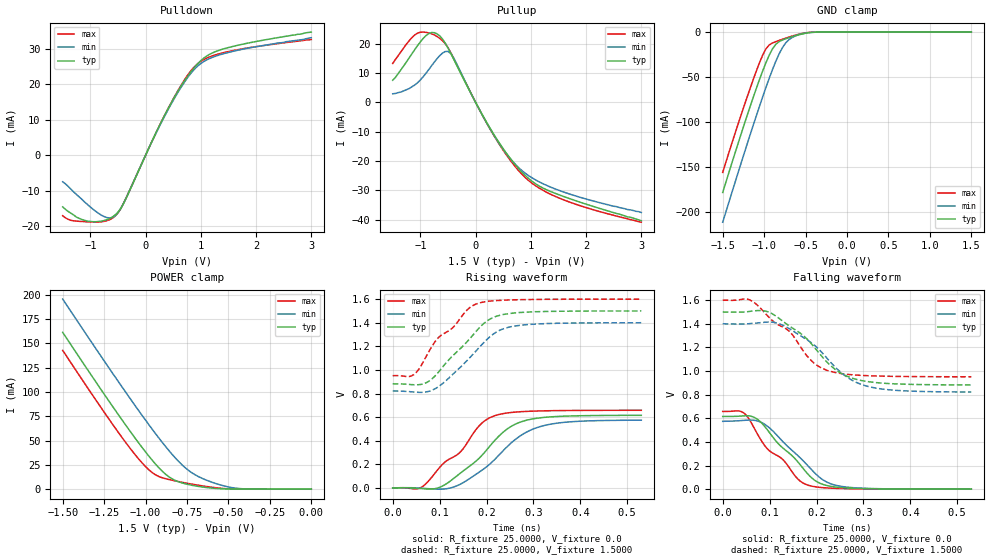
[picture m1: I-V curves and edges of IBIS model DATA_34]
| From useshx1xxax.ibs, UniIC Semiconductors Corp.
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|When TDQS is enabled, NU_TDQS is a output with terminal resistance;
|When TDQS is disabled, NU_TDQS is a DM;
|   Model DATA_34
[Model]  DATA_34
Model_type   I/O
Polarity   Non-Inverting
Enable   Active-High
Vinl =   0.600000V
Vinh =   0.900000V
Vmeas =   0.750000V
Rref =   25.0000000
Vref =   0.7500000V
C_comp   1.3900pF   1.3640pF   1.5600pF
[Temperature Range]   25.0000   0.1250k   -55.0000
[Voltage Range]   1.5000V   1.4000V   1.6000V
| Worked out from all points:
|   slope of the pulldown table from 0 to 0.225 V, typ, clamps not added: 29.8 ohm
|   slope of the pullup table from 0 to 0.225 V, typ, clamps not added: 29.6 ohm
|   GND clamp passes 1 mA (typ) near -0.48 V on its own axis
|   POWER clamp passes 1 mA (typ) near -0.59 V on its own axis
|   rising waveform, R_fixture 25.0000, V_fixture 0.0: 20-80 % time 98.2ps typ, 102ps min, 93ps max; typ from 0 V to 0.615 V
|   rising waveform, R_fixture 25.0000, V_fixture 1.5000: 20-80 % time 86.9ps typ, 86.9ps min, 83.4ps max; typ from 0.882 V to 1.5 V
|   falling waveform, R_fixture 25.0000, V_fixture 0.0: 20-80 % time 85.5ps typ, 87.2ps min, 84.7ps max; typ from 0.615 V to 0 V
|   falling waveform, R_fixture 25.0000, V_fixture 1.5000: 20-80 % time 99ps typ, 97.4ps min, 95.9ps max; typ from 1.5 V to 0.882 V
[Pulldown]
|Voltage   I(typ)   I(min)   I(max)
-1.5V     -14.6mA    -7.5mA     -17.1mA
-1.35V    -16.4mA    -9.6mA     -18.4mA
-1.05V    -18.61mA   -13.95mA   -18.83mA
-750mV    -18.45mA   -17.34mA   -18.69mA
-600mV    -17.44mA   -17.58mA   -17.78mA
-400mV    -13.69mA   -13.61mA   -13.63mA
450mV     14.38mA    14.09mA    14.45mA
700mV     20.91mA    20.57mA    21.2mA
900mV     25.09mA    24.56mA    25.26mA
1.1V      27.97mA    26.89mA    27.4mA
1.4V      30mA       28.64mA    28.94mA
3V        34.8mA     33.2mA     32.7mA
[Pullup]
|Voltage   I(typ)   I(min)   I(max)
-1.5V     7.5mA      2.9mA      13.2mA
-1.2V     15.18mA    4.7mA      21mA
-1.05V    19.29mA    6.66mA     23.54mA
-850mV    23.36mA    11.08mA    23.61mA
-700mV    23.33mA    14.78mA    22.43mA
-550mV    20.17mA    17.27mA    19.98mA
-450mV    16.69mA    16.62mA    16.92mA
350mV     -11.5mA    -11.77mA   -11.88mA
650mV     -19.65mA   -19.65mA   -20.28mA
950mV     -25.77mA   -24.83mA   -26.46mA
1.7V      -32.77mA   -31.21mA   -33.95mA
3V        -40.3mA    -37.5mA    -40.8mA
[GND_clamp]
|Voltage   I(typ)   I(min)   I(max)
-1.5V     -178.7mA   -211.8mA   -156.3mA
-1.22V    -97.06mA   -129.1mA   -76.4mA
-1.1V     -64.25mA   -94.83mA   -44.79mA
-1.02V    -43.87mA   -72.78mA   -26.14mA
-980mV    -34.46mA   -62.12mA   -18.9mA
-940mV    -25.94mA   -51.8mA    -14.39mA
-860mV    -13.68mA   -32.73mA   -10.66mA
-780mV    -8.804mA   -17.43mA   -8.022mA
-700mV    -6.175mA   -8.381mA   -5.548mA
-580mV    -2.935mA   -2.858mA   -2.33mA
-380mV    -108.7uA   -140.3uA   -50.06uA
1.5V      1.623nA    90.12nA    166.1pA
[POWER_clamp]
|Voltage   I(typ)   I(min)   I(max)
-1.5V     161.3mA    195.6mA    142.8mA
-1.22V    90.37mA    124.5mA    71.87mA
-1.04V    47.2mA     80.43mA    30.73mA
-980mV    33.96mA    66.31mA    19.9mA
-940mV    25.82mA    57.16mA    14.73mA
-880mV    15.49mA    44.03mA    10.81mA
-840mV    10.61mA    35.86mA    9.21mA
-760mV    5.492mA    21.96mA    6.413mA
-700mV    3.357mA    14.68mA    4.567mA
-520mV    282.1uA    3.064mA    565.6uA
-400mV    16.23uA    287.1uA    24.34uA
0V        1.623nA    18.77nA    210.2pA
[Ramp]
| variable   typ   min   max
dV/dt_r  0.3694/99.9524p   0.3451/0.1035n   0.3949/93.7965p
dV/dt_f  0.3712/0.1005n   0.3474/99.1792p   0.3895/97.3597p
R_load = 25.0000
[Rising Waveform]
R_fixture= 25.0000
V_fixture= 0.0
V_fixture_min= 0.0
V_fixture_max= 0.0
|time   V(typ)   V(min)   V(max)
0s        0V         0V         0V
60ps      -5.059mV   -2.078mV   2.719mV
105ps     13.96mV    -10.01mV   195.7mV
150ps     143.2mV    44.4mV     331mV
185ps     254.4mV    135.8mV    529.3mV
220ps     413mV      251.4mV    615.1mV
265ps     546.6mV    421.6mV    643.6mV
320ps     596.5mV    525.8mV    652.9mV
390ps     610.7mV    563.1mV    656.4mV
530ps     615.1mV    574.1mV    657.9mV
[Rising Waveform]
R_fixture= 25.0000
V_fixture= 1.5000
V_fixture_min= 1.4000
V_fixture_max= 1.6000
|time   V(typ)   V(min)   V(max)
0s        882.1mV    822.2mV    951.1mV
45ps      874mV      812.6mV    960.1mV
75ps      898.8mV    816.2mV    1.14V
95ps      969.1mV    851.1mV    1.263V
130ps     1.127V     969.6mV    1.365V
160ps     1.245V     1.085V     1.513V
180ps     1.336V     1.171V     1.561V
210ps     1.436V     1.29V      1.584V
255ps     1.48V      1.368V     1.593V
530ps     1.5V       1.4V       1.6V
[Falling Waveform]
R_fixture= 25.0000
V_fixture= 0.0
V_fixture_min= 0.0
V_fixture_max= 0.0
|time   V(typ)   V(min)   V(max)
0s        615.1mV    574.1mV    657.9mV
45ps      620.4mV    582.2mV    645.1mV
75ps      588.4mV    576.4mV    459.8mV
95ps      503.7mV    534.1mV    342.3mV
125ps     359.6mV    416mV      261.9mV
160ps     232mV      284.8mV    86.36mV
180ps     134.6mV    205mV      36.23mV
215ps     38.58mV    75.45mV    12.37mV
255ps     12.74mV    22.24mV    5.288mV
530ps     0V         0V         0V
[Falling Waveform]
R_fixture= 25.0000
V_fixture= 1.5000
V_fixture_min= 1.4000
V_fixture_max= 1.6000
|time   V(typ)   V(min)   V(max)
0s        1.5V       1.4V       1.6V
55ps      1.503V     1.4V       1.606V
100ps     1.496V     1.414V     1.449V
145ps     1.373V     1.351V     1.324V
180ps     1.27V      1.264V     1.126V
200ps     1.178V     1.203V     1.051V
225ps     1.065V     1.096V     1.002V
270ps     948mV      935.5mV    970.3mV
315ps     907.3mV    864.4mV    959.6mV
530ps     882.1mV    822.2mV    951.1mV
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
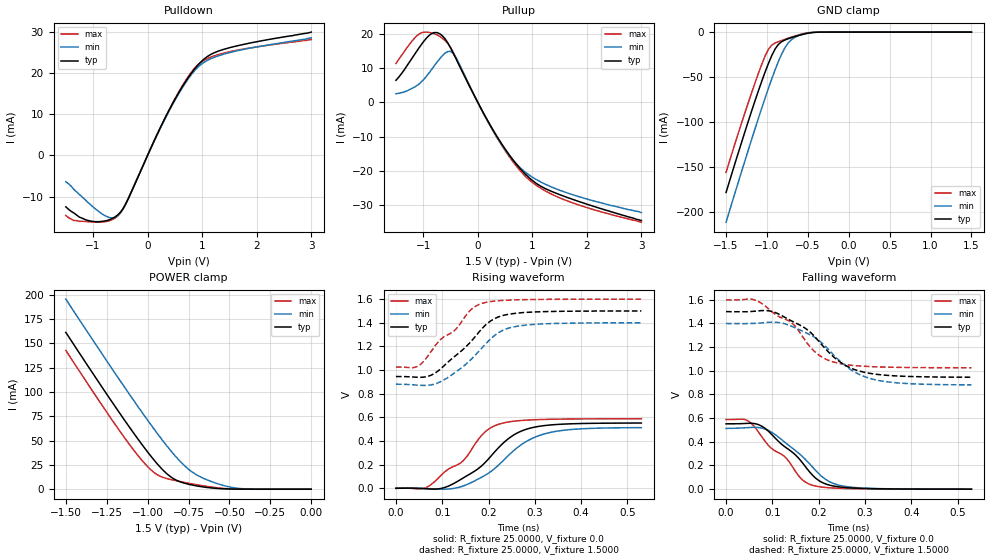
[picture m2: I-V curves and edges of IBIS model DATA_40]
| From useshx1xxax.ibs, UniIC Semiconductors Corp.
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|   Model DATA_40
[Model]  DATA_40
Model_type   I/O
Polarity   Non-Inverting
Enable   Active-High
Vinl =   0.600000V
Vinh =   0.900000V
Vmeas =   0.750000V
Rref =   25.000000
Vref =   0.7500000V
C_comp   1.3900pF   1.3640pF   1.5600pF
[Temperature Range]   25.0000   0.1250k   -55.0000
[Voltage Range]   1.5000V   1.4000V   1.6000V
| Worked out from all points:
|   slope of the pulldown table from 0 to 0.225 V, typ, clamps not added: 34.7 ohm
|   slope of the pullup table from 0 to 0.225 V, typ, clamps not added: 34.4 ohm
|   GND clamp passes 1 mA (typ) near -0.48 V on its own axis
|   POWER clamp passes 1 mA (typ) near -0.59 V on its own axis
|   rising waveform, R_fixture 25.0000, V_fixture 0.0: 20-80 % time 95.5ps typ, 99.1ps min, 91.3ps max; typ from 0 V to 0.552 V
|   rising waveform, R_fixture 25.0000, V_fixture 1.5000: 20-80 % time 86.4ps typ, 84.6ps min, 83.2ps max; typ from 0.946 V to 1.5 V
|   falling waveform, R_fixture 25.0000, V_fixture 0.0: 20-80 % time 85.1ps typ, 85.8ps min, 83.6ps max; typ from 0.552 V to 0 V
|   falling waveform, R_fixture 25.0000, V_fixture 1.5000: 20-80 % time 95.2ps typ, 94.5ps min, 94.5ps max; typ from 1.5 V to 0.946 V
[Pulldown]
|Voltage   I(typ)   I(min)   I(max)
-1.5V     -12.5mA    -6.4mA     -14.6mA
-1.35V    -14mA      -8.3mA     -15.8mA
-1.05V    -15.94mA   -11.94mA   -16.13mA
-750mV    -15.82mA   -14.85mA   -16.03mA
-600mV    -14.97mA   -15.08mA   -15.26mA
-400mV    -11.78mA   -11.71mA   -11.73mA
450mV     12.37mA    12.12mA    12.43mA
700mV     17.98mA    17.68mA    18.23mA
900mV     21.56mA    21.1mA     21.7mA
1.1V      24.01mA    23.07mA    23.5mA
1.4V      25.73mA    24.56mA    24.82mA
3V        29.9mA     28.5mA     28.1mA
[Pullup]
|Voltage   I(typ)   I(min)   I(max)
-1.5V     6.4mA      2.5mA      11.3mA
-1.05V    16.48mA    5.69mA     20.16mA
-850mV    20mA       9.46mA     20.25mA
-700mV    20.03mA    12.63mA    19.26mA
-550mV    17.36mA    14.8mA     17.18mA
-450mV    14.37mA    14.29mA    14.57mA
350mV     -9.897mA   -10.12mA   -10.22mA
650mV     -16.9mA    -16.89mA   -17.44mA
900mV     -21.4mA    -20.74mA   -22.01mA
1.2V      -24.88mA   -23.62mA   -25.52mA
1.65V     -27.83mA   -26.5mA    -28.83mA
3V        -34.5mA    -32.2mA    -35mA
[GND_clamp]
|Voltage   I(typ)   I(min)   I(max)
-1.5V     -178.7mA   -211.8mA   -156.3mA
-1.22V    -97.06mA   -129.1mA   -76.4mA
-1.1V     -64.25mA   -94.83mA   -44.79mA
-1.02V    -43.87mA   -72.78mA   -26.14mA
-980mV    -34.46mA   -62.12mA   -18.9mA
-940mV    -25.94mA   -51.8mA    -14.39mA
-860mV    -13.68mA   -32.73mA   -10.66mA
-780mV    -8.804mA   -17.43mA   -8.022mA
-700mV    -6.175mA   -8.381mA   -5.548mA
-580mV    -2.935mA   -2.858mA   -2.33mA
-380mV    -108.7uA   -140.3uA   -50.06uA
1.5V      1.623nA    90.12nA    166.1pA
[POWER_clamp]
|Voltage   I(typ)   I(min)   I(max)
-1.5V     161.3mA    195.6mA    142.8mA
-1.22V    90.37mA    124.5mA    71.87mA
-1.04V    47.2mA     80.43mA    30.73mA
-980mV    33.96mA    66.31mA    19.9mA
-940mV    25.82mA    57.16mA    14.73mA
-880mV    15.49mA    44.03mA    10.81mA
-840mV    10.61mA    35.86mA    9.21mA
-760mV    5.492mA    21.96mA    6.413mA
-700mV    3.357mA    14.68mA    4.567mA
-520mV    282.1uA    3.064mA    565.6uA
-400mV    16.23uA    287.1uA    24.34uA
0V        1.623nA    18.77nA    210.2pA
[Ramp]
| variable   typ   min   max
dV/dt_r  0.3315/96.9880p   0.3085/0.1005n   0.3529/92.4923p
dV/dt_f  0.3332/96.7909p   0.3122/96.3373p   0.3450/94.7585p
R_load = 25.0000
[Rising Waveform]
R_fixture= 25.0000
V_fixture= 0.0
V_fixture_min= 0.0
V_fixture_max= 0.0
|time   V(typ)   V(min)   V(max)
0s        0V         0V         0V
65ps      -4.097mV   -1.793mV   6.117mV
110ps     13.43mV    -6.823mV   153mV
145ps     86.52mV    19.03mV    232.1mV
180ps     172.9mV    82.84mV    423.9mV
200ps     248.7mV    128.3mV    499.6mV
225ps     356.9mV    209.1mV    545.3mV
270ps     482.4mV    366.5mV    573.1mV
325ps     532.1mV    464.6mV    582.7mV
530ps     551.8mV    512.9mV    588mV
[Rising Waveform]
R_fixture= 25.0000
V_fixture= 1.5000
V_fixture_min= 1.4000
V_fixture_max= 1.6000
|time   V(typ)   V(min)   V(max)
0s        945.6mV    881.1mV    1.025V
45ps      939mV      872.7mV    1.028V
80ps      963.9mV    877.7mV    1.179V
95ps      1.004V     898.7mV    1.253V
140ps     1.157V     1.014V     1.398V
165ps     1.254V     1.1V       1.52V
190ps     1.367V     1.205V     1.568V
225ps     1.454V     1.324V     1.587V
270ps     1.484V     1.375V     1.594V
530ps     1.5V       1.4V       1.6V
[Falling Waveform]
R_fixture= 25.0000
V_fixture= 0.0
V_fixture_min= 0.0
V_fixture_max= 0.0
|time   V(typ)   V(min)   V(max)
0s        551.8mV    512.9mV    588mV
45ps      555.8mV    519.4mV    581.8mV
80ps      525.2mV    512.8mV    427.5mV
100ps     456.3mV    477.2mV    338.4mV
130ps     349.4mV    386.4mV    261.6mV
165ps     222.5mV    275.4mV    78.27mV
190ps     105.4mV    173.1mV    29.33mV
225ps     32.55mV    59.73mV    11.23mV
265ps     11.65mV    19.21mV    4.969mV
530ps     0V         0V         0V
[Falling Waveform]
R_fixture= 25.0000
V_fixture= 1.5000
V_fixture_min= 1.4000
V_fixture_max= 1.6000
|time   V(typ)   V(min)   V(max)
0s        1.5V       1.4V       1.6V
60ps      1.503V     1.4V       1.601V
110ps     1.486V     1.409V     1.467V
145ps     1.414V     1.37V      1.394V
175ps     1.348V     1.317V     1.234V
200ps     1.251V     1.259V     1.134V
230ps     1.126V     1.143V     1.076V
270ps     1.022V     1.007V     1.047V
325ps     970.3mV    921.9mV    1.033V
530ps     945.6mV    881.1mV    1.025V
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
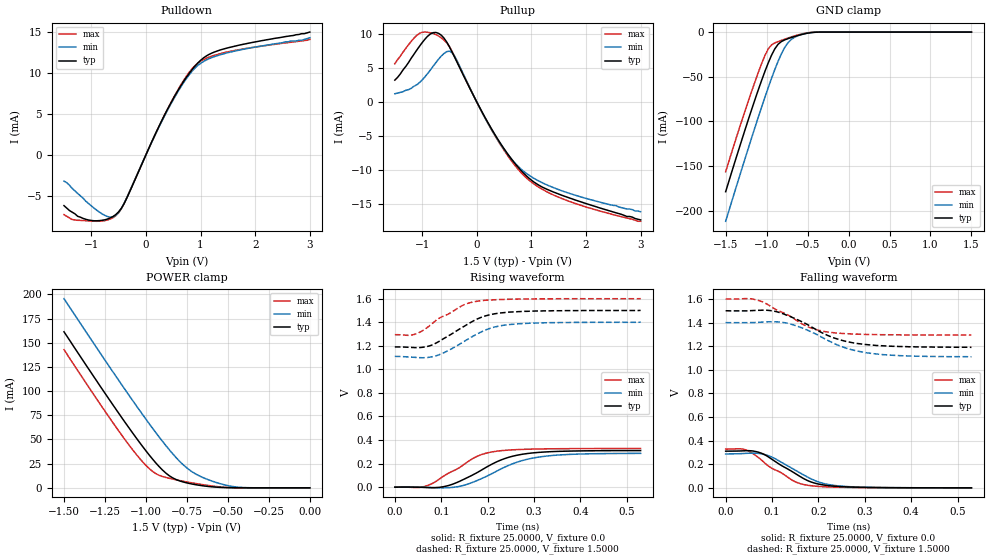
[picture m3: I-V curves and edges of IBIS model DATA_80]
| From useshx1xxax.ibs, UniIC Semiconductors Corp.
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|   Model DATA_80
[Model]  DATA_80
Model_type   I/O
Polarity   Non-Inverting
Enable   Active-High
Vinl =   0.600000V
Vinh =   0.900000V
Vmeas =   0.750000V
Rref =   25.000000
Vref =   0.7500000V
C_comp   1.3900pF   1.3640pF   1.5600pF
[Temperature Range]   25.0000   0.1250k   -55.0000
[Voltage Range]   1.5000V   1.4000V   1.6000V
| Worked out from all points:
|   slope of the pulldown table from 0 to 0.225 V, typ, clamps not added: 68.5 ohm
|   slope of the pullup table from 0 to 0.225 V, typ, clamps not added: 67.8 ohm
|   GND clamp passes 1 mA (typ) near -0.48 V on its own axis
|   POWER clamp passes 1 mA (typ) near -0.59 V on its own axis
|   rising waveform, R_fixture 25.0000, V_fixture 0.0: 20-80 % time 95.2ps typ, 100ps min, 83ps max; typ from 0 V to 0.311 V
|   rising waveform, R_fixture 25.0000, V_fixture 1.5000: 20-80 % time 82.7ps typ, 81.9ps min, 74.4ps max; typ from 1.19 V to 1.5 V
|   falling waveform, R_fixture 25.0000, V_fixture 0.0: 20-80 % time 79.2ps typ, 80.5ps min, 74.5ps max; typ from 0.311 V to 0 V
|   falling waveform, R_fixture 25.0000, V_fixture 1.5000: 20-80 % time 101ps typ, 101ps min, 86.8ps max; typ from 1.5 V to 1.19 V
[Pulldown]
|Voltage   I(typ)   I(min)   I(max)
-1.5V     -6.2mA     -3.2mA     -7.3mA
-1.35V    -7mA       -4.1mA     -7.9mA
-1.05V    -7.96mA    -5.94mA    -8.06mA
-750mV    -7.929mA   -7.4mA     -8.027mA
-550mV    -7.276mA   -7.386mA   -7.422mA
-400mV    -5.963mA   -5.93mA    -5.941mA
400mV     5.625mA    5.507mA    5.645mA
700mV     9.07mA     8.922mA    9.2mA
900mV     10.85mA    10.61mA    10.91mA
1.1V      12.05mA    11.57mA    11.78mA
1.4V      12.89mA    12.3mA     12.43mA
3V        15mA       14.3mA     14.1mA
[Pullup]
|Voltage   I(typ)   I(min)   I(max)
-1.5V     3.2mA      1.2mA      5.6mA
-1.05V    8.15mA     2.83mA     10.05mA
-850mV    9.96mA     4.68mA     10.14mA
-700mV    10.06mA    6.26mA     9.673mA
-550mV    8.786mA    7.375mA    8.672mA
-450mV    7.293mA    7.21mA     7.393mA
350mV     -5.007mA   -5.121mA   -5.172mA
650mV     -8.527mA   -8.517mA   -8.803mA
900mV     -10.77mA   -10.43mA   -11.08mA
1.2V      -12.49mA   -11.85mA   -12.81mA
1.6V      -13.81mA   -13.15mA   -14.3mA
3V        -17.3mA    -16.1mA    -17.5mA
[GND_clamp]
|Voltage   I(typ)   I(min)   I(max)
-1.5V     -178.7mA   -211.8mA   -156.3mA
-1.22V    -97.06mA   -129.1mA   -76.4mA
-1.1V     -64.25mA   -94.83mA   -44.79mA
-1.02V    -43.87mA   -72.78mA   -26.14mA
-980mV    -34.46mA   -62.12mA   -18.9mA
-940mV    -25.94mA   -51.8mA    -14.39mA
-860mV    -13.68mA   -32.73mA   -10.66mA
-780mV    -8.804mA   -17.43mA   -8.022mA
-700mV    -6.175mA   -8.381mA   -5.548mA
-580mV    -2.935mA   -2.858mA   -2.33mA
-380mV    -108.7uA   -140.3uA   -50.06uA
1.5V      1.623nA    90.12nA    166.1pA
[POWER_clamp]
|Voltage   I(typ)   I(min)   I(max)
-1.5V     161.3mA    195.6mA    142.8mA
-1.22V    90.37mA    124.5mA    71.87mA
-1.04V    47.2mA     80.43mA    30.73mA
-980mV    33.96mA    66.31mA    19.9mA
-940mV    25.82mA    57.16mA    14.73mA
-880mV    15.49mA    44.03mA    10.81mA
-840mV    10.61mA    35.86mA    9.21mA
-760mV    5.492mA    21.96mA    6.413mA
-700mV    3.357mA    14.68mA    4.567mA
-520mV    282.1uA    3.064mA    565.6uA
-400mV    16.23uA    287.1uA    24.34uA
0V        1.623nA    18.77nA    210.2pA
[Ramp]
| variable   typ   min   max
dV/dt_r  0.1867/96.3613p   0.1724/0.1014n   0.1969/84.0483p
dV/dt_f  0.1860/0.1017n   0.1746/0.1023n   0.1836/86.9300p
R_load = 25.0000
[Rising Waveform]
R_fixture= 25.0000
V_fixture= 0.0
V_fixture_min= 0.0
V_fixture_max= 0.0
|time   V(typ)   V(min)   V(max)
0s        0V         0V         0V
60ps      -1.695mV   -493.9uV   2.263mV
80ps      -4.597mV   -2.933mV   29.64mV
110ps     8.321mV    -5.31mV    105.9mV
140ps     50.43mV    7.167mV    167.9mV
175ps     118.5mV    52.53mV    257.2mV
215ps     206.5mV    126.5mV    302.6mV
265ps     272.2mV    214mV      319mV
320ps     297.8mV    260.6mV    324.7mV
530ps     310.6mV    286.7mV    328.1mV
[Rising Waveform]
R_fixture= 25.0000
V_fixture= 1.5000
V_fixture_min= 1.4000
V_fixture_max= 1.6000
|time   V(typ)   V(min)   V(max)
0s        1.19V      1.11V      1.294V
30ps      1.187V     1.105V     1.288V
45ps      1.184V     1.101V     1.3V
65ps      1.19V      1.099V     1.34V
90ps      1.225V     1.116V     1.419V
150ps     1.366V     1.238V     1.549V
185ps     1.439V     1.315V     1.582V
215ps     1.471V     1.359V     1.59V
265ps     1.489V     1.386V     1.596V
530ps     1.5V       1.4V       1.6V
[Falling Waveform]
R_fixture= 25.0000
V_fixture= 0.0
V_fixture_min= 0.0
V_fixture_max= 0.0
|time   V(typ)   V(min)   V(max)
0s        310.6mV    286.7mV    328.1mV
40ps      313.7mV    291.2mV    325.5mV
55ps      313.7mV    293.9mV    299mV
75ps      296.2mV    289.2mV    242.9mV
100ps     241.2mV    259.9mV    164.7mV
145ps     133.7mV    161.1mV    61.42mV
175ps     64.59mV    94.72mV    23.03mV
210ps     24.75mV    38.09mV    9.616mV
255ps     8.96mV     12.71mV    3.973mV
530ps     0V         0V         0V
[Falling Waveform]
R_fixture= 25.0000
V_fixture= 1.5000
V_fixture_min= 1.4000
V_fixture_max= 1.6000
|time   V(typ)   V(min)   V(max)
0s        1.5V       1.4V       1.6V
60ps      1.502V     1.4V       1.598V
80ps      1.505V     1.404V     1.575V
110ps     1.492V     1.406V     1.507V
135ps     1.458V     1.393V     1.463V
175ps     1.386V     1.338V     1.368V
220ps     1.291V     1.249V     1.32V
265ps     1.236V     1.177V     1.305V
315ps     1.209V     1.138V     1.299V
530ps     1.19V      1.11V      1.294V
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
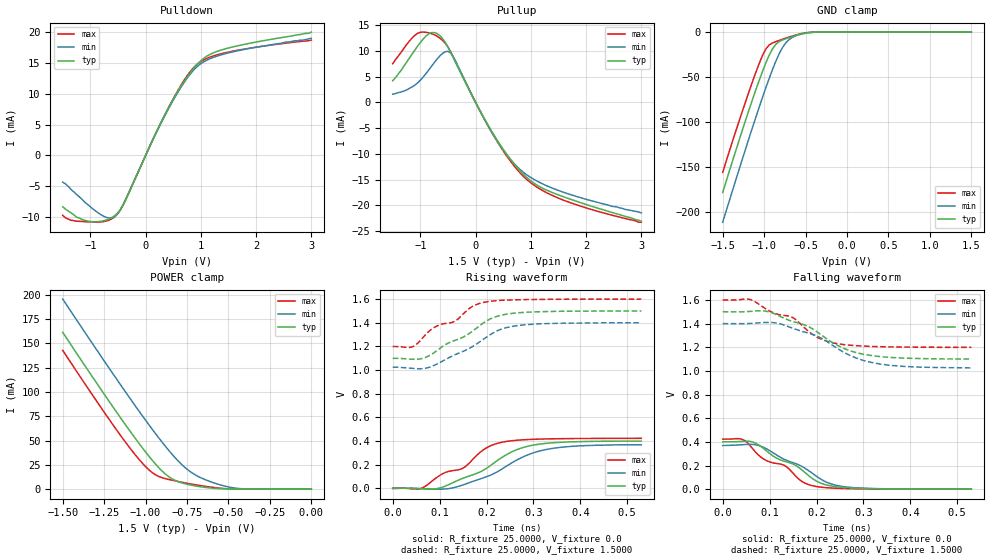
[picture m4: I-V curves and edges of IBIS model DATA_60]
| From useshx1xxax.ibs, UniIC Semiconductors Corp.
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|   Model DATA_60
[Model]  DATA_60
Model_type   I/O
Polarity   Non-Inverting
Enable   Active-High
Vinl =   0.600000V
Vinh =   0.900000V
Vmeas =   0.750000V
Rref =   25.000000
Vref =   0.7500000V
C_comp   1.3900pF   1.3640pF   1.5600pF
[Temperature Range]   25.0000   0.1250k   -55.0000
[Voltage Range]   1.5000V   1.4000V   1.6000V
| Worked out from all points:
|   slope of the pulldown table from 0 to 0.225 V, typ, clamps not added: 51.6 ohm
|   slope of the pullup table from 0 to 0.225 V, typ, clamps not added: 51.1 ohm
|   GND clamp passes 1 mA (typ) near -0.48 V on its own axis
|   POWER clamp passes 1 mA (typ) near -0.59 V on its own axis
|   rising waveform, R_fixture 25.0000, V_fixture 0.0: 20-80 % time 114ps typ, 114ps min, 107ps max; typ from 0 V to 0.4 V
|   rising waveform, R_fixture 25.0000, V_fixture 1.5000: 20-80 % time 103ps typ, 102ps min, 97.8ps max; typ from 1.1 V to 1.5 V
|   falling waveform, R_fixture 25.0000, V_fixture 0.0: 20-80 % time 100ps typ, 102ps min, 97.9ps max; typ from 0.4 V to 0 V
|   falling waveform, R_fixture 25.0000, V_fixture 1.5000: 20-80 % time 117ps typ, 114ps min, 110ps max; typ from 1.5 V to 1.1 V
[Pulldown]
|Voltage   I(typ)   I(min)   I(max)
-1.5V     -8.3mA     -4.3mA     -9.7mA
-1.35V    -9.3mA     -5.5mA     -10.5mA
-1.05V    -10.62mA   -7.93mA    -10.75mA
-750mV    -10.56mA   -9.88mA    -10.7mA
-550mV    -9.688mA   -9.828mA   -9.879mA
-400mV    -7.919mA   -7.874mA   -7.889mA
400mV     7.472mA    7.315mA    7.497mA
700mV     12.06mA    11.86mA    12.23mA
900mV     14.44mA    14.12mA    14.52mA
1.1V      16.05mA    15.41mA    15.7mA
1.35V     17.04mA    16.26mA    16.45mA
3V        20mA       19mA       18.7mA
[Pullup]
|Voltage   I(typ)   I(min)   I(max)
-1.5V     4.2mA      1.6mA      7.5mA
-1.05V    10.91mA    3.78mA     13.41mA
-850mV    13.3mA     6.26mA     13.52mA
-700mV    13.39mA    8.37mA     12.88mA
-550mV    11.67mA    9.845mA    11.52mA
-450mV    9.677mA    9.584mA    9.81mA
350mV     -6.65mA    -6.802mA   -6.868mA
650mV     -11.33mA   -11.32mA   -11.7mA
900mV     -14.33mA   -13.88mA   -14.74mA
1.15V     -16.34mA   -15.52mA   -16.75mA
1.6V      -18.39mA   -17.52mA   -19.05mA
3V        -23.1mA    -21.5mA    -23.3mA
[GND_clamp]
|Voltage   I(typ)   I(min)   I(max)
-1.5V     -178.7mA   -211.8mA   -156.3mA
-1.22V    -97.06mA   -129.1mA   -76.4mA
-1.1V     -64.25mA   -94.83mA   -44.79mA
-1.02V    -43.87mA   -72.78mA   -26.14mA
-980mV    -34.46mA   -62.12mA   -18.9mA
-940mV    -25.94mA   -51.8mA    -14.39mA
-860mV    -13.68mA   -32.73mA   -10.66mA
-780mV    -8.804mA   -17.43mA   -8.022mA
-700mV    -6.175mA   -8.381mA   -5.548mA
-580mV    -2.935mA   -2.858mA   -2.33mA
-380mV    -108.7uA   -140.3uA   -50.06uA
1.5V      1.623nA    90.12nA    166.1pA
[POWER_clamp]
|Voltage   I(typ)   I(min)   I(max)
-1.5V     161.3mA    195.6mA    142.8mA
-1.22V    90.37mA    124.5mA    71.87mA
-1.04V    47.2mA     80.43mA    30.73mA
-980mV    33.96mA    66.31mA    19.9mA
-940mV    25.82mA    57.16mA    14.73mA
-880mV    15.49mA    44.03mA    10.81mA
-840mV    10.61mA    35.86mA    9.21mA
-760mV    5.492mA    21.96mA    6.413mA
-700mV    3.357mA    14.68mA    4.567mA
-520mV    282.1uA    3.064mA    565.6uA
-400mV    16.23uA    287.1uA    24.34uA
0V        1.623nA    18.77nA    210.2pA
[Ramp]
| variable   typ   min   max
dV/dt_r  0.2403/0.1158n   0.2221/0.1165n   0.2538/0.1078n
dV/dt_f  0.2406/0.1185n   0.2256/0.1151n   0.2412/0.1122n
R_load = 25.0000
[Rising Waveform]
R_fixture= 25.0000
V_fixture= 0.0
V_fixture_min= 0.0
V_fixture_max= 0.0
|time   V(typ)   V(min)   V(max)
0s        0V         0V         0V
60ps      -3.534mV   -1.416mV   -627uV
100ps     2.819mV    -6.638mV   108.6mV
150ps     85.75mV    29.27mV    171.3mV
195ps     157.5mV    91.55mV    330.4mV
235ps     267mV      169.1mV    391.5mV
280ps     347.7mV    269.9mV    411mV
335ps     383.4mV    334.2mV    418.5mV
410ps     396.1mV    361.3mV    421.7mV
530ps     399.8mV    369mV      422.8mV
[Rising Waveform]
R_fixture= 25.0000
V_fixture= 1.5000
V_fixture_min= 1.4000
V_fixture_max= 1.6000
|time   V(typ)   V(min)   V(max)
0s        1.099V     1.024V     1.199V
40ps      1.092V     1.015V     1.194V
70ps      1.107V     1.016V     1.299V
95ps      1.166V     1.052V     1.374V
130ps     1.247V     1.125V     1.408V
170ps     1.328V     1.198V     1.538V
195ps     1.403V     1.265V     1.573V
230ps     1.462V     1.344V     1.589V
270ps     1.485V     1.378V     1.594V
530ps     1.5V       1.4V       1.6V
[Falling Waveform]
R_fixture= 25.0000
V_fixture= 0.0
V_fixture_min= 0.0
V_fixture_max= 0.0
|time   V(typ)   V(min)   V(max)
0s        399.8mV    369mV      422.8mV
40ps      403.9mV    375.3mV    423.1mV
65ps      397.1mV    377.7mV    336.5mV
90ps      334.7mV    347.8mV    248.5mV
130ps     237.4mV    254.4mV    203.5mV
165ps     175mV      200mV      76.15mV
195ps     79.5mV     123.1mV    25.82mV
230ps     27.88mV    45.85mV    10.24mV
270ps     10.57mV    16.02mV    4.556mV
530ps     0V         0V         0V
[Falling Waveform]
R_fixture= 25.0000
V_fixture= 1.5000
V_fixture_min= 1.4000
V_fixture_max= 1.6000
|time   V(typ)   V(min)   V(max)
0s        1.5V       1.4V       1.6V
55ps      1.502V     1.4V       1.606V
100ps     1.497V     1.409V     1.506V
150ps     1.417V     1.359V     1.449V
195ps     1.346V     1.304V     1.3V
240ps     1.226V     1.201V     1.233V
285ps     1.154V     1.108V     1.213V
335ps     1.121V     1.058V     1.205V
410ps     1.105V     1.033V     1.2V
530ps     1.099V     1.024V     1.199V
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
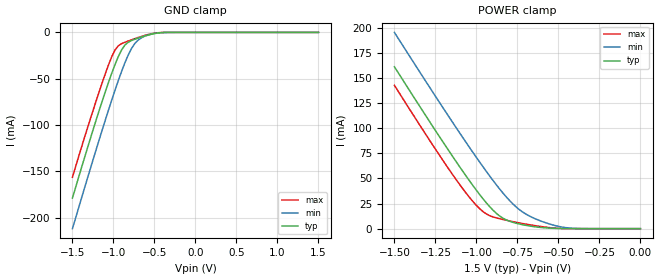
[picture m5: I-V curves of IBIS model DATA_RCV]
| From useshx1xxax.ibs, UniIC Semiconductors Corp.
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|   Model DATA_RCV
[Model]  DATA_RCV
Model_type   Input
Polarity   Non-Inverting
Vinl =   0.600000V
Vinh =   0.900000V
C_comp   1.3900pF   1.3640pF   1.5600pF
[Temperature Range]   25.0000   0.1250k   -55.0000
[Voltage Range]   1.5000V   1.4000V   1.6000V
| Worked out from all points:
|   GND clamp passes 1 mA (typ) near -0.48 V on its own axis
|   POWER clamp passes 1 mA (typ) near -0.59 V on its own axis
[GND_clamp]
|Voltage   I(typ)   I(min)   I(max)
-1.5V     -178.7mA   -211.8mA   -156.3mA
-1.22V    -97.06mA   -129.1mA   -76.4mA
-1.1V     -64.25mA   -94.83mA   -44.79mA
-1.02V    -43.87mA   -72.78mA   -26.14mA
-980mV    -34.46mA   -62.12mA   -18.9mA
-940mV    -25.94mA   -51.8mA    -14.39mA
-860mV    -13.68mA   -32.73mA   -10.66mA
-780mV    -8.804mA   -17.43mA   -8.022mA
-700mV    -6.175mA   -8.381mA   -5.548mA
-580mV    -2.935mA   -2.858mA   -2.33mA
-380mV    -108.7uA   -140.3uA   -50.06uA
1.5V      1.623nA    90.12nA    166.1pA
[POWER_clamp]
|Voltage   I(typ)   I(min)   I(max)
-1.5V     161.3mA    195.6mA    142.8mA
-1.22V    90.37mA    124.5mA    71.87mA
-1.04V    47.2mA     80.43mA    30.73mA
-980mV    33.96mA    66.31mA    19.9mA
-940mV    25.82mA    57.16mA    14.73mA
-880mV    15.49mA    44.03mA    10.81mA
-840mV    10.61mA    35.86mA    9.21mA
-760mV    5.492mA    21.96mA    6.413mA
-700mV    3.357mA    14.68mA    4.567mA
-520mV    282.1uA    3.064mA    565.6uA
-400mV    16.23uA    287.1uA    24.34uA
0V        1.623nA    18.77nA    210.2pA
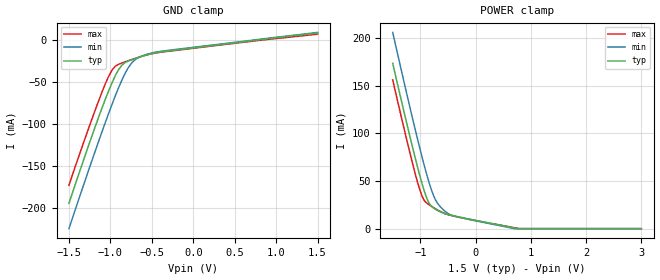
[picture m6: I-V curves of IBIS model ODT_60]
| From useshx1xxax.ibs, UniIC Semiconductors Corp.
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|   Model ODT_60
[Model]  ODT_60
Model_type   Input
Polarity   Non-Inverting
Vinl =   0.600000V
Vinh =   0.900000V
C_comp   1.3900pF   1.3640pF   1.5600pF
[Temperature Range]   25.0000   0.1250k   -55.0000
[Voltage Range]   1.5000V   1.4000V   1.6000V
[GND_clamp]
|Voltage   I(typ)   I(min)   I(max)
-1.5V     -194.4mA   -224.6mA   -173mA
-1.22V    -113.2mA   -142.6mA   -93.18mA
-1.1V     -80.42mA   -108.7mA   -61.44mA
-1.02V    -60mA      -86.87mA   -42.71mA
-980mV    -50.55mA   -76.31mA   -35.43mA
-940mV    -41.97mA   -66.08mA   -30.87mA
-860mV    -29.58mA   -47.17mA   -27.03mA
-780mV    -24.53mA   -31.99mA   -24.25mA
-700mV    -21.68mA   -22.99mA   -21.59mA
-580mV    -17.97mA   -17.28mA   -17.95mA
-380mV    -13.66mA   -13.01mA   -14.08mA
1.5V      8.718mA    9.415mA    7.341mA
[POWER_clamp]
|Voltage   I(typ)   I(min)   I(max)
-1.5V     173.4mA    205.8mA    156mA
-1.16V    89.89mA    120.2mA    72.78mA
-1.06V    66.76mA    96.16mA    50.67mA
-980mV    49.45mA    77.61mA    35.85mA
-920mV    37.89mA    64.33mA    28.93mA
-860mV    28.89mA    51.88mA    25.82mA
-760mV    21.7mA     34.6mA     22.04mA
-680mV    18.79mA    25.97mA    19.36mA
-540mV    15.44mA    17.62mA    15.44mA
-340mV    12.73mA    12.44mA    12.48mA
752.8mV   0A         NA         NA
3V        0A         0A         0A
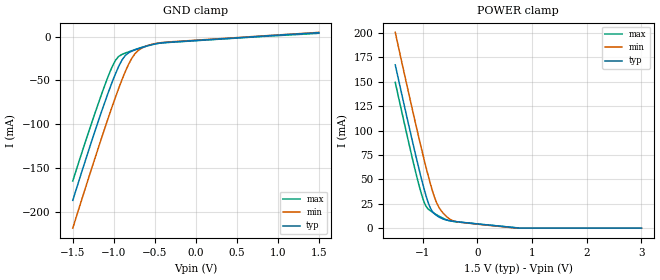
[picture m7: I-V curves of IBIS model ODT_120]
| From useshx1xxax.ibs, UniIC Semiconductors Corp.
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|   Model ODT_120
[Model]  ODT_120
Model_type   Input
Polarity   Non-Inverting
Vinl =   0.600000V
Vinh =   0.900000V
C_comp   1.3900pF   1.3640pF   1.5600pF
[Temperature Range]   25.0000   0.1250k   -55.0000
[Voltage Range]   1.5000V   1.4000V   1.6000V
[GND_clamp]
|Voltage   I(typ)   I(min)   I(max)
-1.5V     -186.6mA   -218.2mA   -164.6mA
-1.22V    -105.1mA   -135.9mA   -84.79mA
-1.1V     -72.33mA   -101.8mA   -53.12mA
-1.02V    -51.93mA   -79.82mA   -34.42mA
-980mV    -42.51mA   -69.21mA   -27.17mA
-940mV    -33.96mA   -58.94mA   -22.63mA
-860mV    -21.64mA   -39.95mA   -18.85mA
-780mV    -16.67mA   -24.71mA   -16.14mA
-700mV    -13.93mA   -15.69mA   -13.57mA
-580mV    -10.46mA   -10.07mA   -10.15mA
-380mV    -6.894mA   -6.589mA   -7.078mA
1.5V      4.361mA    4.712mA    3.67mA
[POWER_clamp]
|Voltage   I(typ)   I(min)   I(max)
-1.5V     167.4mA    200.7mA    149.4mA
-1.16V    82.75mA    114.9mA    65.08mA
-1.06V    59.27mA    90.69mA    42.75mA
-980mV    41.7mA     71.96mA    27.88mA
-920mV    29.97mA    58.51mA    20.98mA
-860mV    20.85mA    45.88mA    17.9mA
-760mV    13.6mA     28.28mA    14.23mA
-680mV    10.8mA     19.41mA    11.69mA
-540mV    7.94mA     10.79mA    8.142mA
-360mV    6.501mA    6.422mA    6.378mA
752.9mV   0A         NA         NA
3V        0A         0A         0A
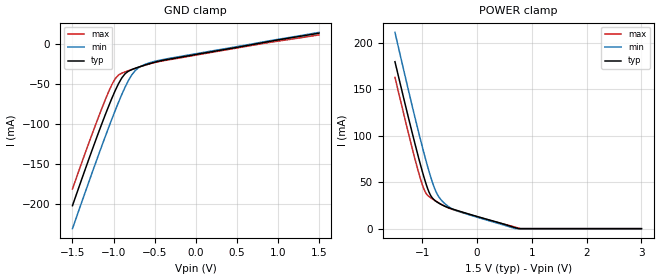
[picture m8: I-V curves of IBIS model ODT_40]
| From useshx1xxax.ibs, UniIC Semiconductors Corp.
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|   Model ODT_40
[Model]  ODT_40
Model_type   Input
Polarity   Non-Inverting
Vinl =   0.600000V
Vinh =   0.900000V
C_comp   1.3900pF   1.3640pF   1.5600pF
[Temperature Range]   25.0000   0.1250k   -55.0000
[Voltage Range]   1.5000V   1.4000V   1.6000V
[GND_clamp]
|Voltage   I(typ)   I(min)   I(max)
-1.5V     -202.2mA   -230.9mA   -181.3mA
-1.18V    -110.1mA   -138mA     -90.72mA
-1.1V     -88.5mA    -115.7mA   -69.76mA
-1.02V    -68.05mA   -93.92mA   -50.99mA
-980mV    -58.58mA   -83.4mA    -43.69mA
-940mV    -49.98mA   -73.22mA   -39.1mA
-860mV    -37.52mA   -54.4mA    -35.21mA
-780mV    -32.38mA   -39.27mA   -32.35mA
-700mV    -29.41mA   -30.28mA   -29.59mA
-580mV    -25.47mA   -24.47mA   -25.74mA
-420mV    -21.2mA    -20.22mA   -21.8mA
1.5V      13.07mA    14.11mA    11.01mA
[POWER_clamp]
|Voltage   I(typ)   I(min)   I(max)
-1.5V     179.4mA    210.9mA    162.5mA
-1.16V    97.05mA    125.6mA    80.5mA
-1.06V    74.27mA    101.6mA    58.59mA
-980mV    57.21mA    83.27mA    43.83mA
-920mV    45.82mA    70.16mA    36.89mA
-860mV    36.94mA    57.9mA     33.73mA
-760mV    29.8mA     40.94mA    29.83mA
-680mV    26.77mA    32.55mA    27.01mA
-560mV    23.37mA    25.39mA    23.24mA
-320mV    18.7mA     18.2mA     18.34mA
752.8mV   0A         NA         NA
3V        0A         0A         0A
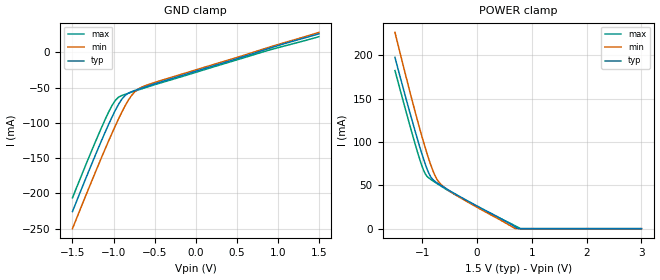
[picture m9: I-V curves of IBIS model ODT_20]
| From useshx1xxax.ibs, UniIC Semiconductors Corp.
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|   Model ODT_20
[Model]  ODT_20
Model_type   Input
Polarity   Non-Inverting
Vinl =   0.600000V
Vinh =   0.900000V
C_comp   1.3900pF   1.3640pF   1.5600pF
[Temperature Range]   25.0000   0.1250k   -55.0000
[Voltage Range]   1.5000V   1.4000V   1.6000V
[GND_clamp]
|Voltage   I(typ)   I(min)   I(max)
-1.5V     -225.7mA   -250mA     -206.3mA
-1.18V    -134.4mA   -158.5mA   -115.8mA
-1.02V    -92.18mA   -115.1mA   -75.78mA
-980mV    -82.64mA   -104.7mA   -68.42mA
-940mV    -73.96mA   -94.66mA   -63.76mA
-900mV    -66.63mA   -85.05mA   -61.36mA
-820mV    -57.99mA   -67.96mA   -58.14mA
-740mV    -54.15mA   -55.83mA   -55.07mA
-660mV    -50.97mA   -49.62mA   -52.02mA
-500mV    -44.83mA   -42.85mA   -46.07mA
860mV     4.232mA    5.866mA    1.877mA
1.5V      26.1mA     28.13mA    22.04mA
[POWER_clamp]
|Voltage   I(typ)   I(min)   I(max)
-1.5V     197.5mA    226.3mA    182.3mA
-1.16V    118.6mA    141.5mA    103.7mA
-980mV    80.61mA    100.3mA    67.74mA
-940mV    73.14mA    91.79mA    62.5mA
-880mV    63.62mA    79.76mA    58.35mA
-780mV    55.02mA    62.71mA    54mA
-700mV    51.44mA    53.83mA    50.7mA
-600mV    47.44mA    47.78mA    46.7mA
0V        26.1mA     24.56mA    25.4mA
600mV     5.719mA    3.635mA    6.418mA
752.6mV   0A         NA         NA
3V        0A         0A         0A
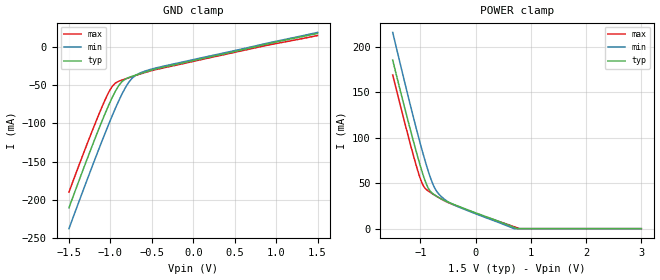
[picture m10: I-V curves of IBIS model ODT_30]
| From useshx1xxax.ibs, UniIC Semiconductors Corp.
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|   Model ODT_30
[Model]  ODT_30
Model_type   Input
Polarity   Non-Inverting
Vinl =   0.600000V
Vinh =   0.900000V
C_comp   1.3900pF   1.3640pF   1.5600pF
[Temperature Range]   25.0000   0.1250k   -55.0000
[Voltage Range]   1.5000V   1.4000V   1.6000V
[GND_clamp]
|Voltage   I(typ)   I(min)   I(max)
-1.5V     -210.1mA   -237.3mA   -189.6mA
-1.22V    -129.3mA   -156.2mA   -109.9mA
-1.1V     -96.58mA   -122.6mA   -78.07mA
-1.02V    -76.1mA    -101mA     -59.26mA
-980mV    -66.61mA   -90.5mA    -51.94mA
-940mV    -57.98mA   -80.37mA   -47.33mA
-860mV    -45.45mA   -61.62mA   -43.38mA
-780mV    -40.22mA   -46.55mA   -40.44mA
-700mV    -37.13mA   -37.58mA   -37.59mA
-580mV    -32.95mA   -31.64mA   -33.51mA
-420mV    -28.12mA   -26.81mA   -28.98mA
1.5V      17.42mA    18.79mA    14.69mA
[POWER_clamp]
|Voltage   I(typ)   I(min)   I(max)
-1.5V     185.5mA    216mA      169.1mA
-1.16V    104.2mA    130.9mA    88.23mA
-1.06V    81.8mA     107.1mA    66.52mA
-980mV    65mA       88.93mA    51.8mA
-920mV    53.77mA    75.99mA    44.84mA
-860mV    45mA       63.92mA    41.63mA
-760mV    37.89mA    47.29mA    37.62mA
-680mV    34.73mA    39.13mA    34.65mA
-560mV    30.91mA    32.22mA    30.57mA
-220mV    22.52mA    21.72mA    22.05mA
752.7mV   0A         NA         NA
3V        0A         0A         0A
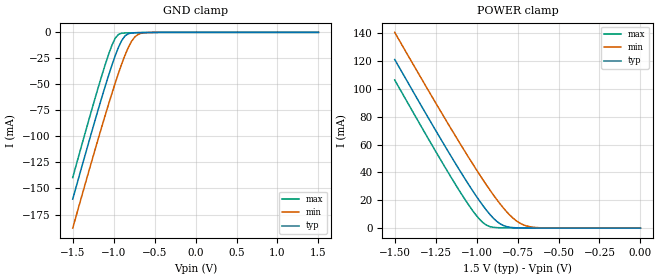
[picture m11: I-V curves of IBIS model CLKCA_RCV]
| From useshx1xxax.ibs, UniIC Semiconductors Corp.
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|   Model CLKCA_RCV
[Model]  CLKCA_RCV
Model_type   Input
Polarity   Non-Inverting
Vinl =   0.600000V
Vinh =   0.900000V
C_comp   0.9500pF   0.9400pF   0.9600pF
[Temperature Range]   25.0000   0.1250k   -55.0000
[Voltage Range]   1.5000V   1.4000V   1.6000V
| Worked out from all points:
|   GND clamp passes 1 mA (typ) near -0.80 V on its own axis
|   POWER clamp passes 1 mA (typ) near -0.81 V on its own axis
[GND_clamp]
|Voltage   I(typ)   I(min)   I(max)
-1.5V     -160.2mA   -188.1mA   -139.5mA
-1.18V    -71.75mA   -99.93mA   -50.65mA
-1.1V     -50.85mA   -78.75mA   -30.14mA
-1.02V    -31.17mA   -58.27mA   -12.1mA
-980mV    -22.15mA   -48.41mA   -5.435mA
-940mV    -14.08mA   -38.91mA   -1.827mA
-900mV    -7.546mA   -29.9mA    -781.4uA
-820mV    -1.257mA   -14.27mA   -468.9uA
-740mV    -379.1uA   -4.209mA   -341.4uA
-660mV    -225.7uA   -793.6uA   -226.4uA
-540mV    -89.94uA   -101uA     -83.45uA
1.5V      576.8pA    1.895nA    84.47pA
[POWER_clamp]
|Voltage   I(typ)   I(min)   I(max)
-1.5V     121.2mA    140.7mA    106.5mA
-1.2V     60.32mA    80.1mA     45.21mA
-1.04V    29.74mA    49.19mA    15.2mA
-980mV    19.25mA    38.15mA    6.129mA
-940mV    12.9mA     31.06mA    2.173mA
-900mV    7.429mA    24.28mA    612.4uA
-860mV    3.386mA    17.94mA    286.9uA
-820mV    1.189mA    12.23mA    212uA
-760mV    247.9uA    5.486mA    155.9uA
-680mV    76.02uA    1.138mA    97.13uA
-560mV    16.64uA    86.06uA    30.21uA
0V        576.8pA    388.7pA    116.9pA
